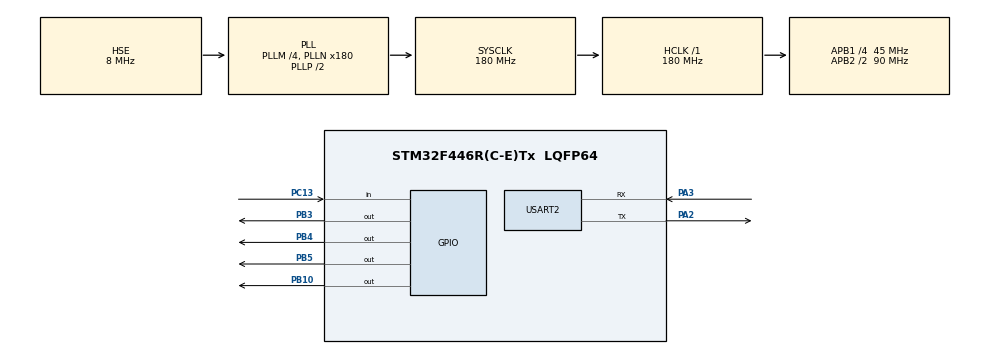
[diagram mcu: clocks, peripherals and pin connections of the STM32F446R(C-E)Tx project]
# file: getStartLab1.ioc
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FREERTOS.Tasks01=Task1,24,128,StartTask1,Default,NULL,Dynamic,NULL,NULL;Task2,24,128,StartTask2,Default,NULL,Dynamic,NULL,NULL;Task3,24,128,StartTask3,Default,NULL,Dynamic,NULL,NULL;Task4,24,128,StartTask4,Default,NULL,Dynamic,NULL,NULL;Task5,24,128,StartTask5,Default,NULL,Dynamic,NULL,NULL
FREERTOS.configUSE_NEWLIB_REENTRANT=1
Mcu.Family=STM32F4
Mcu.Name=STM32F446R(C-E)Tx
Mcu.Package=LQFP64
NVIC.PriorityGroup=NVIC_PRIORITYGROUP_4
NVIC.TIM6_DAC_IRQn=true\:15\:0\:false\:false\:true\:false\:false\:true\:true
NVIC.TimeBase=TIM6_DAC_IRQn
NVIC.TimeBaseIP=TIM6
PA13.Mode=Serial_Wire
PA13.Signal=SYS_JTMS-SWDIO
PA14.Mode=Serial_Wire
PA14.Signal=SYS_JTCK-SWCLK
PA2.Mode=Asynchronous
PA2.Signal=USART2_TX
PA3.Mode=Asynchronous
PA3.Signal=USART2_RX
PB10.Signal=GPIO_Output
PB3.Signal=GPIO_Output
PB4.Signal=GPIO_Output
PB5.Signal=GPIO_Output
PC13.Signal=GPIO_Input
PH0-OSC_IN.Mode=HSE-External-Oscillator
PH0-OSC_IN.Signal=RCC_OSC_IN
PH1-OSC_OUT.Mode=HSE-External-Oscillator
PH1-OSC_OUT.Signal=RCC_OSC_OUT
ProjectManager.HeapSize=0x200
ProjectManager.StackSize=0x400
ProjectManager.TargetToolchain=STM32CubeIDE
RCC.48MHZClocksFreq_Value=84000000
RCC.AHBFreq_Value=180000000
RCC.APB1CLKDivider=RCC_HCLK_DIV4
RCC.APB1Freq_Value=45000000
RCC.APB1TimFreq_Value=90000000
RCC.APB2CLKDivider=RCC_HCLK_DIV2
RCC.APB2Freq_Value=90000000
RCC.APB2TimFreq_Value=180000000
RCC.CortexFreq_Value=180000000
RCC.FLatency-AdvancedSettings=FLASH_LATENCY_5
RCC.HCLKFreq_Value=180000000
RCC.HSE_VALUE=8000000
RCC.HSI_VALUE=16000000
RCC.PLLM=4
RCC.PLLN=180
RCC.PLLSourceVirtual=RCC_PLLSOURCE_HSE
RCC.SYSCLKFreq_VALUE=180000000
RCC.SYSCLKSource=RCC_SYSCLKSOURCE_PLLCLK
RCC.USBFreq_Value=180000000
RCC.VCOOutputFreq_Value=360000000
USART2.VirtualMode=VM_ASYNC
VP_FREERTOS_VS_CMSIS_V2.Mode=CMSIS_V2
VP_SYS_VS_tim6.Mode=TIM6
board=NUCLEO-F446RE

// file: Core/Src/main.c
/* USER CODE BEGIN Header */
/**
  ******************************************************************************
  * @file           : main.c
  * @brief          : Main program body
  ******************************************************************************
  * @attention
  *
  * Copyright (c) 2024 STMicroelectronics.
  * All rights reserved.
  *
  * This software is licensed under terms that can be found in the LICENSE file
  * in the root directory of this software component.
  * If no LICENSE file comes with this software, it is provided AS-IS.
  *
  ******************************************************************************
  */
/* USER CODE END Header */
#include "main.h"
#include "cmsis_os.h"

UART_HandleTypeDef huart2;

/* Definitions for Green */
osThreadId_t GreenHandle;
const osThreadAttr_t Green_attributes = {
  .name = "Green",
  .stack_size = 128 * 4,
  .priority = (osPriority_t) osPriorityNormal,
};
/* Definitions for Orange */
osThreadId_t OrangeHandle;
const osThreadAttr_t Orange_attributes = {
  .name = "Orange",
  .stack_size = 128 * 4,
  .priority = (osPriority_t) osPriorityNormal,
};
/* Definitions for Red */
osThreadId_t RedHandle;
const osThreadAttr_t Red_attributes = {
  .name = "Red",
  .stack_size = 128 * 4,
  .priority = (osPriority_t) osPriorityNormal,
};
/* Definitions for Task4 */
osThreadId_t Task4Handle;
const osThreadAttr_t Task4_attributes = {
  .name = "Task4",
  .stack_size = 128 * 4,
  .priority = (osPriority_t) osPriorityNormal,
};
/* Definitions for Task5 */
osThreadId_t Task5Handle;
const osThreadAttr_t Task5_attributes = {
  .name = "Task5",
  .stack_size = 128 * 4,
  .priority = (osPriority_t) osPriorityNormal,
};
/* Definitions for Task6 */
osThreadId_t Task6Handle;
const osThreadAttr_t Task6_attributes = {
  .name = "Task6",
  .stack_size = 128 * 4,
  .priority = (osPriority_t) osPriorityNormal,
};
/* Definitions for ButtonPressed */
osEventFlagsId_t ButtonPressedHandle;
const osEventFlagsAttr_t ButtonPressed_attributes = {
  .name = "ButtonPressed"
};
/* Definitions for CanButtonPress */
osEventFlagsId_t CanButtonPressHandle;
const osEventFlagsAttr_t CanButtonPress_attributes = {
  .name = "CanButtonPress"
};

void SystemClock_Config(void);
static void MX_GPIO_Init(void);
static void MX_USART2_UART_Init(void);
void GreenLight(void *argument);
void OrangeLight(void *argument);
void RedLight(void *argument);
void GreenPieton(void *argument);
void RedPieton(void *argument);
void Button(void *argument);

/* USER CODE BEGIN 0 */
volatile int flag = 0;

/* USER CODE END 0 */

int main(void)
{

  /* MCU Configuration--------------------------------------------------------*/

  /* Reset of all peripherals, Initializes the Flash interface and the Systick. */
  HAL_Init();

  /* Configure the system clock */
  SystemClock_Config();

  /* Initialize all configured peripherals */
  MX_GPIO_Init();
  MX_USART2_UART_Init();

  /* Init scheduler */
  osKernelInitialize();

  /* Create the thread(s) */
  /* creation of Green */
  GreenHandle = osThreadNew(GreenLight, NULL, &Green_attributes);

  /* creation of Orange */
  OrangeHandle = osThreadNew(OrangeLight, NULL, &Orange_attributes);

  /* creation of Red */
  RedHandle = osThreadNew(RedLight, NULL, &Red_attributes);

  /* creation of Task4 */
  Task4Handle = osThreadNew(GreenPieton, NULL, &Task4_attributes);

  /* creation of Task5 */
  Task5Handle = osThreadNew(RedPieton, NULL, &Task5_attributes);

  /* creation of Task6 */
  Task6Handle = osThreadNew(Button, NULL, &Task6_attributes);

  /* Create the event(s) */
  /* creation of ButtonPressed */
  ButtonPressedHandle = osEventFlagsNew(&ButtonPressed_attributes);

  /* creation of CanButtonPress */
  CanButtonPressHandle = osEventFlagsNew(&CanButtonPress_attributes);

  /* Start scheduler */
  osKernelStart();

  /* We should never get here as control is now taken by the scheduler */
  /* Infinite loop */
  while (1)
  {

  }
}

void SystemClock_Config(void)
{
  RCC_OscInitTypeDef RCC_OscInitStruct = {0};
  RCC_ClkInitTypeDef RCC_ClkInitStruct = {0};

  /** Configure the main internal regulator output voltage
  */
  __HAL_RCC_PWR_CLK_ENABLE();
  __HAL_PWR_VOLTAGESCALING_CONFIG(PWR_REGULATOR_VOLTAGE_SCALE1);

  /** Initializes the RCC Oscillators according to the specified parameters
  * in the RCC_OscInitTypeDef structure.
  */
  RCC_OscInitStruct.OscillatorType = RCC_OSCILLATORTYPE_HSE;
  RCC_OscInitStruct.HSEState = RCC_HSE_ON;
  RCC_OscInitStruct.PLL.PLLState = RCC_PLL_ON;
  RCC_OscInitStruct.PLL.PLLSource = RCC_PLLSOURCE_HSE;
  RCC_OscInitStruct.PLL.PLLM = 4;
  RCC_OscInitStruct.PLL.PLLN = 180;
  RCC_OscInitStruct.PLL.PLLP = RCC_PLLP_DIV2;
  RCC_OscInitStruct.PLL.PLLQ = 2;
  RCC_OscInitStruct.PLL.PLLR = 2;
  if (HAL_RCC_OscConfig(&RCC_OscInitStruct) != HAL_OK)
  {
    Error_Handler();
  }

  /** Activate the Over-Drive mode
  */
  if (HAL_PWREx_EnableOverDrive() != HAL_OK)
  {
    Error_Handler();
  }

  /** Initializes the CPU, AHB and APB buses clocks
  */
  RCC_ClkInitStruct.ClockType = RCC_CLOCKTYPE_HCLK|RCC_CLOCKTYPE_SYSCLK
                              |RCC_CLOCKTYPE_PCLK1|RCC_CLOCKTYPE_PCLK2;
  RCC_ClkInitStruct.SYSCLKSource = RCC_SYSCLKSOURCE_PLLCLK;
  RCC_ClkInitStruct.AHBCLKDivider = RCC_SYSCLK_DIV1;
  RCC_ClkInitStruct.APB1CLKDivider = RCC_HCLK_DIV4;
  RCC_ClkInitStruct.APB2CLKDivider = RCC_HCLK_DIV2;

  if (HAL_RCC_ClockConfig(&RCC_ClkInitStruct, FLASH_LATENCY_5) != HAL_OK)
  {
    Error_Handler();
  }
}

static void MX_USART2_UART_Init(void)
{

  huart2.Instance = USART2;
  huart2.Init.BaudRate = 115200;
  huart2.Init.WordLength = UART_WORDLENGTH_8B;
  huart2.Init.StopBits = UART_STOPBITS_1;
  huart2.Init.Parity = UART_PARITY_NONE;
  huart2.Init.Mode = UART_MODE_TX_RX;
  huart2.Init.HwFlowCtl = UART_HWCONTROL_NONE;
  huart2.Init.OverSampling = UART_OVERSAMPLING_16;
  if (HAL_UART_Init(&huart2) != HAL_OK)
  {
    Error_Handler();
  }

}

static void MX_GPIO_Init(void)
{
  GPIO_InitTypeDef GPIO_InitStruct = {0};

  /* GPIO Ports Clock Enable */
  __HAL_RCC_GPIOC_CLK_ENABLE();
  __HAL_RCC_GPIOH_CLK_ENABLE();
  __HAL_RCC_GPIOA_CLK_ENABLE();
  __HAL_RCC_GPIOB_CLK_ENABLE();
  __HAL_RCC_GPIOD_CLK_ENABLE();

  /*Configure GPIO pin Output Level */
  HAL_GPIO_WritePin(GPIOB, GPIO_PIN_10|GPIO_PIN_3|GPIO_PIN_4|GPIO_PIN_5
                          |GPIO_PIN_6|GPIO_PIN_7, GPIO_PIN_RESET);

  /*Configure GPIO pin : PC13 */
  GPIO_InitStruct.Pin = GPIO_PIN_13;
  GPIO_InitStruct.Mode = GPIO_MODE_INPUT;
  GPIO_InitStruct.Pull = GPIO_NOPULL;
  HAL_GPIO_Init(GPIOC, &GPIO_InitStruct);

  /*Configure GPIO pins : PB10 PB3 PB4 PB5
                           PB6 PB7 */
  GPIO_InitStruct.Pin = GPIO_PIN_10|GPIO_PIN_3|GPIO_PIN_4|GPIO_PIN_5
                          |GPIO_PIN_6|GPIO_PIN_7;
  GPIO_InitStruct.Mode = GPIO_MODE_OUTPUT_PP;
  GPIO_InitStruct.Pull = GPIO_NOPULL;
  GPIO_InitStruct.Speed = GPIO_SPEED_FREQ_LOW;
  HAL_GPIO_Init(GPIOB, &GPIO_InitStruct);

  /*Configure GPIO pin : PD2 */
  GPIO_InitStruct.Pin = GPIO_PIN_2;
  GPIO_InitStruct.Mode = GPIO_MODE_INPUT;
  GPIO_InitStruct.Pull = GPIO_NOPULL;
  HAL_GPIO_Init(GPIOD, &GPIO_InitStruct);

}

void GreenLight(void *argument)
{
  /* USER CODE BEGIN 5 */
  /* Infinite loop */
  for(;;)
  {

      if(flag)
      {
    	  HAL_GPIO_WritePin(GPIOB, GPIO_PIN_3, GPIO_PIN_RESET);
    	  osDelay(17000);
    	  flag = 0;
      }
      HAL_GPIO_WritePin(GPIOB, GPIO_PIN_3, GPIO_PIN_SET);
      osDelay(50);
  }
  /* USER CODE END 5 */
}

void OrangeLight(void *argument)
{
  /* USER CODE BEGIN OrangeLight */
  /* Infinite loop */
  for(;;)
  {
      if(flag)
      {
    	  HAL_GPIO_WritePin(GPIOB, GPIO_PIN_5, GPIO_PIN_SET);
    	  osDelay(3000);
    	  HAL_GPIO_WritePin(GPIOB, GPIO_PIN_5, GPIO_PIN_RESET);
    	  osDelay(12000);
    	  HAL_GPIO_WritePin(GPIOB, GPIO_PIN_5, GPIO_PIN_SET);
    	  osDelay(2000);
    	  HAL_GPIO_WritePin(GPIOB, GPIO_PIN_5, GPIO_PIN_RESET);
    	  flag = 0;
      }
	  HAL_GPIO_WritePin(GPIOB, GPIO_PIN_5, GPIO_PIN_RESET);
  }
  /* USER CODE END OrangeLight */
}

void RedLight(void *argument)
{
  /* USER CODE BEGIN RedLight */
  /* Infinite loop */
  for(;;)
  {
      if(flag)
      {
    	  osDelay(3000);
    	  HAL_GPIO_WritePin(GPIOB, GPIO_PIN_4, GPIO_PIN_SET);
    	  osDelay(14000);
    	  flag = 0;

      }
	  HAL_GPIO_WritePin(GPIOB, GPIO_PIN_4, GPIO_PIN_RESET);
  }
  /* USER CODE END RedLight */
}

void GreenPieton(void *argument)
{
  /* USER CODE BEGIN GreenPieton */
  /* Infinite loop */
  for(;;)
  {
      if(flag)
      {
    	  osDelay(4000);
    	  HAL_GPIO_WritePin(GPIOB, GPIO_PIN_10, GPIO_PIN_SET);
    	  osDelay(10000);
    	  HAL_GPIO_WritePin(GPIOB, GPIO_PIN_10, GPIO_PIN_RESET);
    	  flag = 0;
      }
	  HAL_GPIO_WritePin(GPIOB, GPIO_PIN_10, GPIO_PIN_RESET);
  }
  /* USER CODE END GreenPieton */
}

void RedPieton(void *argument)
{
  /* USER CODE BEGIN RedPieton */
  /* Infinite loop */
  for(;;)
  {
      if(flag)
      {
    	  osDelay(4000);
    	  HAL_GPIO_WritePin(GPIOB, GPIO_PIN_6, GPIO_PIN_RESET);
    	  osDelay(10000);
    	  HAL_GPIO_WritePin(GPIOB, GPIO_PIN_6, GPIO_PIN_SET);
    	  flag = 0;
      }
	  HAL_GPIO_WritePin(GPIOB, GPIO_PIN_6, GPIO_PIN_SET);

  }
  /* USER CODE END RedPieton */
}

void Button(void *argument)
{
  /* USER CODE BEGIN Button */
  /* Infinite loop */
  for(;;)
  {
	  while(HAL_GPIO_ReadPin(GPIOC, GPIO_PIN_13));
	  flag = 1;
	  osDelay(500);
  }
  /* USER CODE END Button */
}

void HAL_TIM_PeriodElapsedCallback(TIM_HandleTypeDef *htim)
{
  if (htim->Instance == TIM6) {
    HAL_IncTick();
  }
}

void Error_Handler(void)
{
  __disable_irq();
  while (1)
  {
  }
}
